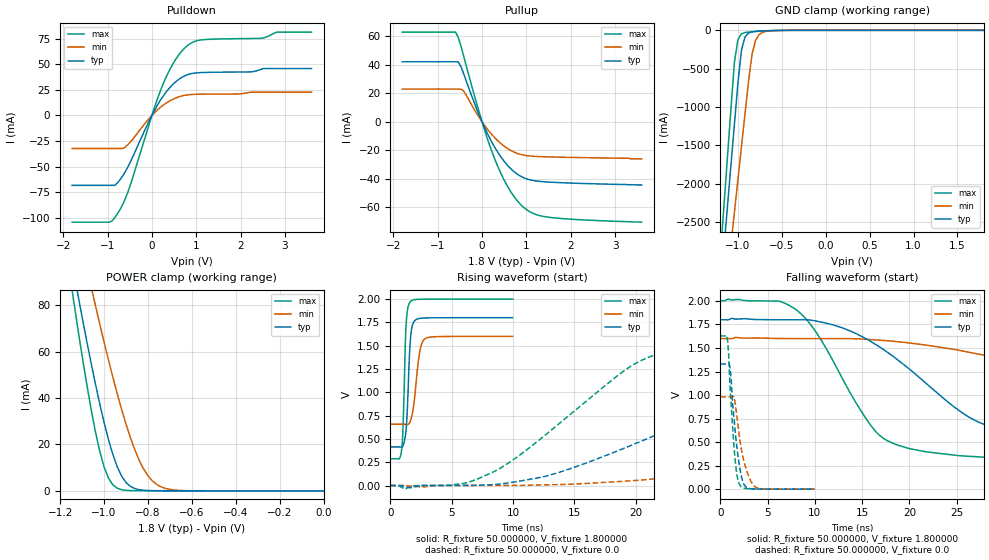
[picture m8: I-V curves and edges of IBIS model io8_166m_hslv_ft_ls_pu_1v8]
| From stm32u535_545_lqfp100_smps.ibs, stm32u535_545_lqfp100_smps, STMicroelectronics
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|   Model io8_166m_hslv_ft_ls_pu_1v8
[Model]  io8_166m_hslv_ft_ls_pu_1v8
Model_type I/O
Polarity   Non-Inverting
Enable   Active-Low
Vinl =   0.540000V
Vinh =   1.260000V
Vmeas =  0.900000V
Cref =   50.000000pF
Rref =   100.000000M
Vref =   0.0V
C_comp   3.358300pF   3.352700pF   3.400300pF
[Temperature Range]   25.000000   0.140000k   -40.000000
[Pullup Reference]   1.800000V   1.600000V   2.000000V
[Pulldown Reference]   0.0V   0.0V   0.0V
[POWER Clamp Reference]   1.800000V   1.600000V   2.000000V
[GND Clamp Reference]   0.0V   0.0V   0.0V
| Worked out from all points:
|   slope of the pulldown table from 0 to 0.27 V, typ, clamps not added: 13.6 ohm
|   slope of the pullup table from 0 to 0.27 V, typ, clamps not added: 15.9 ohm
|   GND clamp passes 1 mA (typ) near -0.51 V on its own axis
|   POWER clamp passes 1 mA (typ) near -0.86 V on its own axis
|   rising waveform, R_fixture 50.000000, V_fixture 1.800000: 20-80 % time 278ps typ, 481ps min, 227ps max; typ from 0.414 V to 1.8 V
|   rising waveform, R_fixture 50.000000, V_fixture 0.0: 20-80 % time 16.1ns typ, 33.4ns min, 9.36ns max; typ from 0 V to 1.33 V
|   falling waveform, R_fixture 50.000000, V_fixture 1.800000: 20-80 % time 11.2ns typ, 27.6ns min, 6.1ns max; typ from 1.8 V to 0.414 V
|   falling waveform, R_fixture 50.000000, V_fixture 0.0: 20-80 % time 789ps typ, 1.05ns min, 623ps max; typ from 1.33 V to 0 V
[Pulldown]
|Voltage   I(typ)   I(min)   I(max)
-1.8V     -68.38mA   -32.32mA   -104.4mA
-960mV    -68.38mA   -32.32mA   -104.4mA
-780mV    -66.08mA   -32.32mA   -96.43mA
-540mV    -50.22mA   -28.51mA   -74.66mA
0V        0A         0A         0A
240mV     18.04mA    9.599mA    29.42mA
480mV     30.68mA    16.02mA    50.95mA
780mV     39.48mA    19.98mA    67.56mA
1.14V     41.99mA    20.78mA    74.01mA
2.46V     45.1mA     22.68mA    75.45mA
2.82V     45.89mA    22.68mA    81.54mA
3.6V      45.89mA    22.68mA    81.54mA
[Pullup]
|Voltage   I(typ)   I(min)   I(max)
-1.8V     42.16mA    23.02mA    63.02mA
-600mV    42.16mA    23.02mA    63.02mA
-540mV    42.16mA    23.02mA    59.54mA
-420mV    34.21mA    21.82mA    46.75mA
0V        630fA      250pA      10fA
300mV     -18.63mA   -11.6mA    -27.18mA
600mV     -31.41mA   -19.24mA   -46.67mA
780mV     -36.41mA   -22mA      -54.88mA
960mV     -39.54mA   -23.51mA   -60.64mA
1.2V      -41.44mA   -24.28mA   -64.93mA
1.56V     -42.42mA   -24.69mA   -67.24mA
3.6V      -44.3mA    -26mA      -70.5mA
[GND_clamp]
|Voltage   I(typ)   I(min)   I(max)
-1.8V     -9.908A    -9.683A    -9.994A
-1.2V     -3.383A    -4.084A    -2.934A
-1.16V    -2.841A    -3.655A    -2.294A
-1.12V    -2.299A    -3.226A    -1.656A
-1.04V    -1.218A    -2.369A    -414.2mA
-1V       -684.7mA   -1.941A    -119.2mA
-960mV    -257.2mA   -1.514A    -45.66mA
-920mV    -87.03mA   -1.089A    -28.93mA
-840mV    -19.35mA   -312.8mA   -18.97mA
-800mV    -13.55mA   -132.4mA   -15.49mA
-720mV    -8.042mA   -25.67mA   -9.491mA
1.8V      0A         13.64nA    0A
[POWER_clamp]
|Voltage   I(typ)   I(min)   I(max)
-1.8V     470.9mA    433.7mA    554.6mA
-1.14V    95.28mA    122.7mA    82.88mA
-1.12V    85mA       114mA      70.34mA
-1.06V    55.55mA    88.43mA    35.73mA
-1.04V    46.38mA    80.17mA    25.83mA
-1V       29.54mA    64.14mA    10.37mA
-940mV    10.43mA    41.88mA    1.177mA
-900mV    3.66mA     28.79mA    250.5uA
-840mV    527.2uA    13.26mA    96.07uA
-800mV    154.2uA    6.55mA     88.1uA
-740mV    59.7uA     1.741mA    70.27uA
0V        0A         18.18nA    0A
[Ramp]
| variable   typ   min   max
dV/dt_r  0.79757/16.06785n   0.58795/33.32307n   0.97651/9.35352n
dV/dt_f  0.83133/11.14119n   0.56483/27.60321n   1.02743/6.09107n
R_load = 50.000000
[Rising Waveform]
R_fixture= 50.000000
V_fixture= 1.800000
V_fixture_min= 1.600000
V_fixture_max= 2.000000
|time   V(typ)   V(min)   V(max)
0s        414.4mV    657.5mV    287.6mV
920.9ps   411.5mV    657.6mV    379mV
1.041ns   428.7mV    657.6mV    636mV
1.221ns   526.2mV    657mV      1.498V
1.301ns   621.3mV    655.6mV    1.744V
1.622ns   1.533V     688.4mV    1.97V
1.842ns   1.735V     803.8mV    1.99V
2.382ns   1.793V     1.419V     1.998V
2.803ns   1.797V     1.572V     1.999V
9.97ns    1.8V       1.6V       2V
[Rising Waveform]
R_fixture= 50.000000
V_fixture= 0.0
V_fixture_min= 0.0
V_fixture_max= 0.0
|time   V(typ)   V(min)   V(max)
0s        425uV      507.6uV    388.2uV
7.207ns   4.411mV    1.318mV    75.72mV
12.81ns   105.7mV    8.437mV    561.4mV
20.42ns   474.3mV    58.98mV    1.34V
28.83ns   915.8mV    199.5mV    1.556V
35.24ns   1.139V     328.5mV    1.597V
45.25ns   1.259V     527.6mV    1.62V
62.86ns   1.313V     793.7mV    1.627V
81.28ns   1.327V     911.3mV    1.628V
199.4ns   1.33V      980.6mV    1.628V
[Falling Waveform]
R_fixture= 50.000000
V_fixture= 1.800000
V_fixture_min= 1.600000
V_fixture_max= 2.000000
|time   V(typ)   V(min)   V(max)
0s        1.8V       1.6V       2V
8.008ns   1.8V       1.6V       1.909V
10.41ns   1.78V      1.6V       1.625V
16.82ns   1.514V     1.583V     574.5mV
25.23ns   838.1mV    1.476V     356.5mV
28.83ns   656.1mV    1.404V     334.7mV
34.83ns   545mV      1.257V     311.6mV
49.65ns   458.8mV    919.3mV    293.7mV
65.67ns   431.2mV    777.5mV    289mV
199.4ns   414.4mV    657.5mV    287.6mV
[Falling Waveform]
R_fixture= 50.000000
V_fixture= 0.0
V_fixture_min= 0.0
V_fixture_max= 0.0
|time   V(typ)   V(min)   V(max)
0s        1.33V      980.6mV    1.628V
740.7ps   1.33V      980.7mV    1.592V
860.9ps   1.335V     980.8mV    1.446V
1.041ns   1.271V     980.7mV    1.051V
1.502ns   687.9mV    951.6mV    379.7mV
1.742ns   447.6mV    773.8mV    155.6mV
2.062ns   221.4mV    523.5mV    44.56mV
2.583ns   36.69mV    262.4mV    8.659mV
3.724ns   1.976mV    21.48mV    2.163mV
9.97ns    425uV      507.6uV    388.2uV
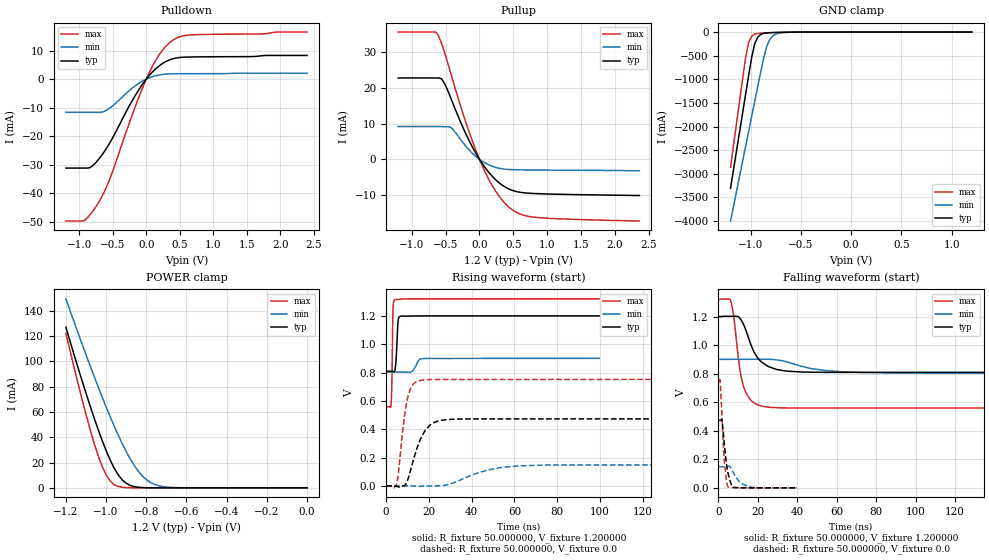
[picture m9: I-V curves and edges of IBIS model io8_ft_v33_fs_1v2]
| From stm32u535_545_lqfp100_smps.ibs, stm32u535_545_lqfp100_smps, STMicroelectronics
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|   Model io8_ft_v33_fs_1v2
[Model]  io8_ft_v33_fs_1v2
Model_type I/O
Polarity   Non-Inverting
Enable   Active-Low
Vinl =   0.360000V
Vinh =   0.840000V
Vmeas =  0.600000V
Cref =   50.000000pF
Rref =   100.000000M
Vref =   0.0V
C_comp   2.887200pF   2.816900pF   2.935200pF
[Temperature Range]   25.000000   0.140000k   -40.000000
[Pullup Reference]   1.200000V   0.900000V   1.320000V
[Pulldown Reference]   0.0V   0.0V   0.0V
[POWER Clamp Reference]   1.200000V   0.900000V   1.320000V
[GND Clamp Reference]   0.0V   0.0V   0.0V
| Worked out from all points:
|   slope of the pulldown table from 0 to 0.18 V, typ, clamps not added: 40.7 ohm
|   slope of the pullup table from 0 to 0.18 V, typ, clamps not added: 39.5 ohm
|   GND clamp passes 1 mA (typ) near -0.51 V on its own axis
|   POWER clamp passes 1 mA (typ) near -0.86 V on its own axis
|   rising waveform, R_fixture 50.000000, V_fixture 1.200000: 20-80 % time 757ps typ, 2.05ns min, 447ps max; typ from 0.809 V to 1.2 V
|   rising waveform, R_fixture 50.000000, V_fixture 0.0: 20-80 % time 6.63ns typ, 16.9ns min, 3.64ns max; typ from 0 V to 0.473 V
|   falling waveform, R_fixture 50.000000, V_fixture 1.200000: 20-80 % time 7.97ns typ, 18.7ns min, 4.69ns max; typ from 1.2 V to 0.809 V
|   falling waveform, R_fixture 50.000000, V_fixture 0.0: 20-80 % time 2.5ns typ, 4.76ns min, 1.85ns max; typ from 0.473 V to 0 V
[Pulldown]
|Voltage   I(typ)   I(min)   I(max)
-1.2V     -31.16mA   -11.61mA   -49.71mA
-920mV    -31.16mA   -11.61mA   -49.48mA
-840mV    -31mA      -11.61mA   -47.54mA
-720mV    -28.32mA   -11.61mA   -43.58mA
-560mV    -22.95mA   -10.37mA   -35.89mA
-200mV    -7.146mA   -2.964mA   -11.89mA
0V        0A         0A         0A
160mV     4.047mA    1.298mA    7.361mA
360mV     6.87mA     1.87mA     13mA
480mV     7.543mA    1.91mA     14.69mA
640mV     7.764mA    1.923mA    15.46mA
2.4V      8.316mA    2.103mA    16.52mA
[Pullup]
|Voltage   I(typ)   I(min)   I(max)
-1.2V     22.75mA    9.164mA    35.58mA
-640mV    22.75mA    9.164mA    35.53mA
-560mV    22.49mA    9.164mA    32.42mA
-520mV    21.33mA    9.097mA    30.17mA
-400mV    15.99mA    8.534mA    22.45mA
-200mV    7.069mA    3.642mA    10.26mA
40mV      -1.16mA    -508.1uA   -1.774mA
240mV     -5.73mA    -2.256mA   -8.953mA
480mV     -8.639mA   -2.877mA   -14.04mA
640mV     -9.31mA    -2.942mA   -15.55mA
880mV     -9.601mA   -2.986mA   -16.29mA
2.36V     -10.1mA    -3.2mA     -17.23mA
[GND_clamp]
|Voltage   I(typ)   I(min)   I(max)
-1.2V     -3.305A    -3.998A    -2.862A
-1.05V    -1.316A    -2.418A    -539.3mA
-1.02V    -921mA     -2.103A    -218.8mA
-990mV    -539.5mA   -1.788A    -87.43mA
-960mV    -252.1mA   -1.474A    -44.36mA
-930mV    -110.5mA   -1.16A     -30.32mA
-870mV    -28.03mA   -549.1mA   -21.09mA
-840mV    -18.43mA   -305.6mA   -18.27mA
-810mV    -13.9mA    -159.7mA   -15.73mA
-780mV    -11.23mA   -82.35mA   -13.37mA
-600mV    -2.976mA   -4.272mA   -3.058mA
1.2V      0A         14.74nA    0A
[POWER_clamp]
|Voltage   I(typ)   I(min)   I(max)
-1.2V     127mA      149.4mA    122.2mA
-1.12V    84.97mA    114mA      70.27mA
-1.06V    55.51mA    88.42mA    35.67mA
-1.02V    37.63mA    72.04mA    17.17mA
-1V       29.51mA    64.13mA    10.3mA
-960mV    15.69mA    48.99mA    2.571mA
-900mV    3.624mA    28.77mA    182.8uA
-840mV    490.7uA    13.24mA    11.35uA
-800mV    116.8uA    6.532mA    1.77uA
-740mV    13.2uA     1.723mA    109.1nA
-620mV    167.3nA    79.35uA    0A
0V        0A         17.84nA    0A
[Ramp]
| variable   typ   min   max
dV/dt_r  0.28374/6.61897n   88.93787m/16.86335n 0.45094/3.62573n
dV/dt_f  0.23461/7.92472n   57.88200m/18.63258n 0.45665/4.67847n
R_load = 50.000000
[Rising Waveform]
R_fixture= 50.000000
V_fixture= 1.200000
V_fixture_min= 0.900000
V_fixture_max= 1.320000
|time   V(typ)   V(min)   V(max)
0s        809mV      803.5mV    558.9mV
2.402ns   809.1mV    803.5mV    592.6mV
2.603ns   809mV      803.5mV    677.3mV
3.203ns   807.6mV    803.5mV    1.252V
4.204ns   822mV      803.5mV    1.316V
5.606ns   1.168V     803.5mV    1.316V
6.607ns   1.196V     803.5mV    1.318V
11.81ns   1.199V     805.8mV    1.32V
17.02ns   1.2V       898.1mV    1.32V
99.7ns    1.2V       900mV      1.32V
[Rising Waveform]
R_fixture= 50.000000
V_fixture= 0.0
V_fixture_min= 0.0
V_fixture_max= 0.0
|time   V(typ)   V(min)   V(max)
0s        7.32uV     -68.34nV   9.968uV
4.805ns   -2.709mV   1.407uV    6.193mV
8.408ns   1.279mV    13.29uV    472.8mV
10.01ns   38.87mV    46.98uV    618mV
12.41ns   165.1mV    -871.3uV   711.8mV
16.02ns   329.7mV    -2.15mV    744.5mV
20.82ns   432.2mV    -49.31uV   750.5mV
29.63ns   469.3mV    11.87mV    751.4mV
62.46ns   472.8mV    141.6mV    751.5mV
199.4ns   472.9mV    148.3mV    751.5mV
[Falling Waveform]
R_fixture= 50.000000
V_fixture= 1.200000
V_fixture_min= 0.900000
V_fixture_max= 1.320000
|time   V(typ)   V(min)   V(max)
0s        1.2V       900mV      1.32V
6.006ns   1.201V     900.3mV    1.316V
7.608ns   1.202V     900.6mV    1.213V
10.01ns   1.199V     900.7mV    914.9mV
12.41ns   1.153V     900.5mV    724.3mV
16.02ns   1.018V     900.5mV    620.5mV
21.22ns   889.2mV    900.5mV    575.5mV
42.84ns   810.9mV    848.9mV    559mV
72.87ns   809mV      808mV      558.9mV
199.4ns   809mV      803.5mV    558.9mV
[Falling Waveform]
R_fixture= 50.000000
V_fixture= 0.0
V_fixture_min= 0.0
V_fixture_max= 0.0
|time   V(typ)   V(min)   V(max)
0s        472.9mV    148.3mV    751.5mV
800.8ps   472.6mV    148.2mV    748.6mV
1.762ns   471.4mV    148.2mV    502mV
2.963ns   308mV      148.2mV    189.6mV
4.164ns   156mV      148.1mV    38.87mV
4.885ns   99.39mV    150mV      6.138mV
7.287ns   4.901mV    112.3mV    1.565mV
10.89ns   1.2mV      39.14mV    388.1uV
15.3ns    414.6uV    8.887mV    131.9uV
39.88ns   7.32uV     -68.34nV   9.968uV
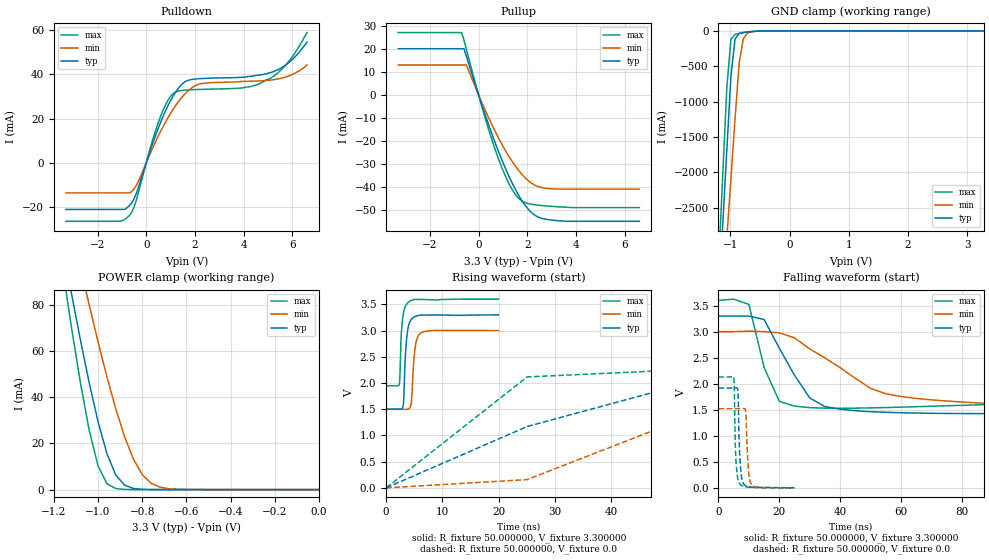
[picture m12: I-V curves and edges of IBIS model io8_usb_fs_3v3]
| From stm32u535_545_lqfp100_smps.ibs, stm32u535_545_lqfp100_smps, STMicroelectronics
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|   Model io8_usb_fs_3v3
[Model]  io8_usb_fs_3v3
Model_type I/O
Polarity   Non-Inverting
Enable   Active-Low
Vinl =   0.990000V
Vinh =   2.310000V
Vmeas =  1.650000V
Cref =   50.000000pF
Rref =   100.000000M
Vref =   0.0V
C_comp   7.156600pF   7.055100pF   7.302500pF
[Temperature Range]   25.000000   0.140000k   -40.000000
[Pullup Reference]   3.300000V   3.000000V   3.600000V
[Pulldown Reference]   0.0V   0.0V   0.0V
[POWER Clamp Reference]   3.300000V   3.000000V   3.600000V
[GND Clamp Reference]   0.0V   0.0V   0.0V
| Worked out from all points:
|   slope of the pulldown table from 0 to 0.495 V, typ, clamps not added: 31.6 ohm
|   slope of the pullup table from 0 to 0.495 V, typ, clamps not added: 32.2 ohm
|   GND clamp passes 1 mA (typ) near -0.45 V on its own axis
|   POWER clamp passes 1 mA (typ) near -0.85 V on its own axis
|   rising waveform, R_fixture 50.000000, V_fixture 3.300000: 20-80 % time 555ps typ, 605ps min, 501ps max; typ from 1.5 V to 3.3 V
|   rising waveform, R_fixture 50.000000, V_fixture 0.0: 20-80 % time 29.3ns typ, 22.8ns min, 15.1ns max; typ from 0 V to 1.92 V
|   falling waveform, R_fixture 50.000000, V_fixture 3.300000: 20-80 % time 10.8ns typ, 26.5ns min, 4.22ns max; typ from 3.3 V to 1.5 V
|   falling waveform, R_fixture 50.000000, V_fixture 0.0: 20-80 % time 702ps typ, 753ps min, 602ps max; typ from 1.92 V to 0 V
[Pulldown]
|Voltage   I(typ)   I(min)   I(max)
-3.3V     -21.13mA   -13.67mA   -26.5mA
-1.1V     -21.13mA   -13.67mA   -26.5mA
-700mV    -19.51mA   -13.67mA   -23.97mA
-500mV    -16.3mA    -11.85mA   -20.09mA
300mV     9.858mA    7.56mA     11.71mA
700mV     21.23mA    16.55mA    24.03mA
1.1V      30.13mA    24.13mA    31.26mA
1.6V      36.71mA    31.28mA    32.85mA
2.3V      38.1mA     35.87mA    33.2mA
5V        40.46mA    37.28mA    37.62mA
5.8V      44.84mA    39.07mA    45.16mA
6.6V      54.6mA     44.2mA     58.9mA
[Pullup]
|Voltage   I(typ)   I(min)   I(max)
-3.3V     20.01mA    12.95mA    27.01mA
-700mV    20.01mA    12.95mA    27.01mA
-600mV    20.01mA    12.95mA    23.76mA
-500mV    16.71mA    12.95mA    19.71mA
200mV     -6.395mA   -4.906mA   -7.458mA
700mV     -21.26mA   -16.19mA   -24.24mA
1.2V      -34.16mA   -25.83mA   -37.46mA
1.5V      -40.71mA   -30.66mA   -42.95mA
1.7V      -44.47mA   -33.42mA   -45.3mA
2.2V      -51.21mA   -38.4mA    -47.39mA
2.7V      -53.72mA   -40.34mA   -48mA
6.6V      -54.72mA   -40.8mA    -48.81mA
[GND_clamp]
|Voltage   I(typ)   I(min)   I(max)
-3.3V     -9.287A    -9.833A    -9.745A
-1.2V     -3.857A    -4.664A    -3.345A
-1.13V    -2.774A    -3.805A    -2.072A
-1.06V    -1.695A    -2.947A    -813.1mA
-990mV    -641.8mA   -2.091A    -120.9mA
-920mV    -113.3mA   -1.238A    -49.89mA
-850mV    -36.8mA    -452mA     -36.31mA
-780mV    -22.65mA   -108.9mA   -26.22mA
-710mV    -15.23mA   -32.27mA   -17.43mA
-570mV    -5.119mA   -7.032mA   -4.907mA
-360mV    -90.45uA   -461.6uA   -25.95uA
3.28V     0A         40.32nA    -16.18nA
[POWER_clamp]
|Voltage   I(typ)   I(min)   I(max)
-3.28V    1.355A     1.167A     1.664A
-1.16V    105.7mA    131.6mA    95.69mA
-1.12V    84.97mA    114mA      70.27mA
-1.08V    65.05mA    96.83mA    46.54mA
-1.04V    46.34mA    80.15mA    25.76mA
-1V       29.51mA    64.13mA    10.3mA
-960mV    15.69mA    48.99mA    2.571mA
-920mV    6.373mA    35.1mA     455.6uA
-840mV    490.7uA    13.24mA    11.36uA
-760mV    27.33uA    2.767mA    754.7nA
-640mV    348.1nA    134.1uA    754.7nA
0V        0A         50.53nA    0A
[Ramp]
| variable   typ   min   max
dV/dt_r  1.15008/11.43050n   0.91140/22.58416n   1.27866/5.89759n
dV/dt_f  1.07808/10.02434n   0.90144/26.36731n   0.99210/3.80624n
R_load = 50.000000
[Rising Waveform]
R_fixture= 50.000000
V_fixture= 3.300000
V_fixture_min= 3.000000
V_fixture_max= 3.600000
|time   V(typ)   V(min)   V(max)
0s        1.503V     1.498V     1.946V
2.322ns   1.503V     1.498V     1.974V
2.683ns   1.505V     1.498V     2.93V
2.963ns   1.54V      1.498V     3.252V
3.684ns   2.894V     1.498V     3.51V
4.404ns   3.203V     1.583V     3.573V
4.725ns   3.241V     2.118V     3.585V
5.285ns   3.274V     2.763V     3.594V
6.286ns   3.298V     2.962V     3.594V
19.94ns   3.3V       3V         3.6V
[Rising Waveform]
R_fixture= 50.000000
V_fixture= 0.0
V_fixture_min= 0.0
V_fixture_max= 0.0
|time   V(typ)   V(min)   V(max)
0s        53.33nV    536nV      167.3nV
25.03ns   1.17V      157.4mV    2.116V
50.05ns   1.898V     1.204V     2.239V
75.08ns   1.945V     1.433V     2.242V
100.1ns   1.951V     1.489V     2.239V
150.2ns   1.949V     1.512V     2.233V
675.7ns   1.932V     1.519V     2.183V
1.026us   1.925V     1.519V     2.161V
1.451us   1.921V     1.519V     2.144V
2.477us   1.915V     1.519V     2.127V
[Falling Waveform]
R_fixture= 50.000000
V_fixture= 3.300000
V_fixture_min= 3.000000
V_fixture_max= 3.600000
|time   V(typ)   V(min)   V(max)
0s        3.3V       3V         3.6V
10.01ns   3.3V       3.01V      3.522V
15.02ns   3.233V     3V         2.312V
20.02ns   2.682V     2.977V     1.661V
30.03ns   1.725V     2.668V     1.54V
35.04ns   1.561V     2.495V     1.53V
50.05ns   1.462V     1.91V      1.535V
65.07ns   1.435V     1.717V     1.558V
180.2ns   1.442V     1.516V     1.727V
2.492us   1.503V     1.498V     1.946V
[Falling Waveform]
R_fixture= 50.000000
V_fixture= 0.0
V_fixture_min= 0.0
V_fixture_max= 0.0
|time   V(typ)   V(min)   V(max)
0s        1.915V     1.519V     2.127V
5.005ns   1.917V     1.519V     2.128V
5.706ns   1.917V     1.52V      556.1mV
6.406ns   1.837V     1.521V     166.2mV
7.007ns   619.8mV    1.52V      74.97mV
7.608ns   199.1mV    1.52V      43.4mV
8.909ns   41.64mV    1.471V     17.53mV
9.81ns    21.83mV    378.9mV    11.25mV
10.91ns   11.15mV    59.91mV    8.202mV
24.92ns   53.33nV    536nV      167.3nV
